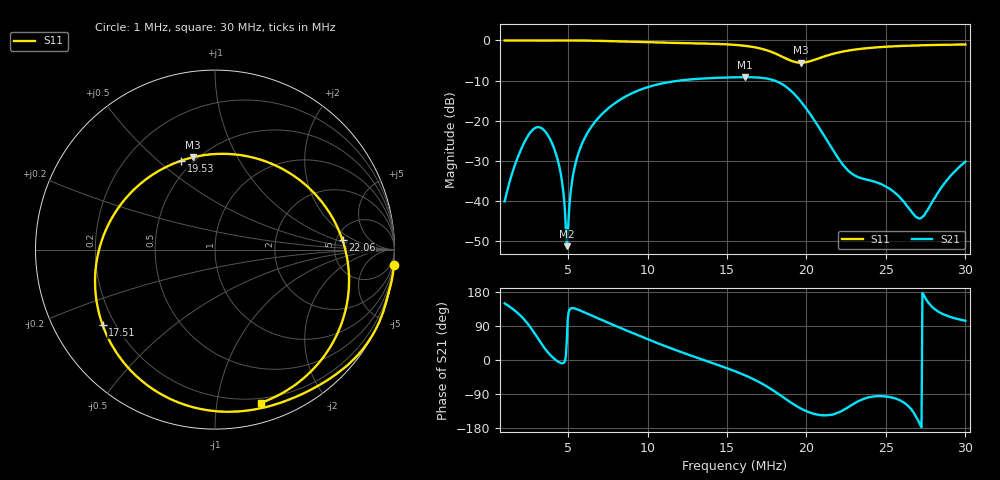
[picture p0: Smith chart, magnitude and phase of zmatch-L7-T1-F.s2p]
# HZ S RI R 50
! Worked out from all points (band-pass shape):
!   505 points, 1 MHz to 30 MHz, reference 50 ohm
!   highest |S21| = -9.13 dB at 16.13 MHz (marker M1); lowest = -51.2 dB at 4.913 MHz (marker M2)
!   |S21| within 3 dB of the highest: 9.625 MHz to 18.91 MHz (9.283 MHz wide, 65.1 % of centre)
!   lowest |S11| = -5.5 dB at 19.64 MHz (marker M3), VSWR 3.25, Z = 23.6 + j33.7 ohm
!   |S11| at or under -10 dB: nowhere
!   S12 and S22 are empty: the file has one direction only
!   S11 on the Smith chart (normalised r, x): 1 MHz: -0, -23; 17.51 MHz: 0.15, -0.30; 19.53 MHz: 0.43, +0.60; 22.06 MHz: 5.70, +1.20; 30 MHz: 0.16, -1.33
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1000000  0.9972 -0.0865  -0.00857 0.00507  0 0  0 0
2265880  0.98 -0.1929  -0.0146 0.0533  0 0  0 0
3301600  0.9577 -0.2741  0.059 0.0564  0 0  0 0
4337320  0.9329 -0.3593  0.0329 -0.00205  0 0  0 0
4625020  0.9235 -0.3838  0.0167 -0.00258  0 0  0 0
4912720  0.9131 -0.4082  0.00183 0.00207  0 0  0 0
5027800  0.9087 -0.4178  -0.00361 0.00499  0 0  0 0
5315500  0.8967 -0.4419  -0.0158 0.0147  0 0  0 0
5833360  0.8727 -0.4844  -0.0314 0.0386  0 0  0 0
7674640  0.7626 -0.6213  -0.0144 0.1507  0 0  0 0
1.066672e7  0.5245 -0.7857  0.2062 0.197  0 0  0 0
1.550008e7  -0.158 -0.8678  0.3027 -0.1724  0 0  0 0
1.613302e7  -0.3098 -0.8004  0.2659 -0.2272  0 0  0 0
1.751398e7  -0.6264 -0.4193  0.1148 -0.3155  0 0  0 0
1.849216e7  -0.6207 0.0788  -0.0352 -0.2821  0 0  0 0
1.952788e7  -0.1881 0.4955  -0.1075 -0.1514  0 0  0 0
1.964296e7  -0.1233 0.5144  -0.1074 -0.1372  0 0  0 0
2.033344e7  0.2485 0.5027  -0.0875 -0.0722  0 0  0 0
2.205964e7  0.7108 0.0519  -0.0244 -0.0221  0 0  0 0
2.51668e7  0.6442 -0.5395  -0.00186 -0.0145  0 0  0 0
2.71807e7  0.4857 -0.7233  -0.00607 -0.0007  0 0  0 0
3.000016e7  0.255 -0.8543  -0.00726 0.0302  0 0  0 0
